VERSION 5.7 ;
  NOWIREEXTENSIONATPIN ON ;
  DIVIDERCHAR "/" ;
  BUSBITCHARS "[]" ;
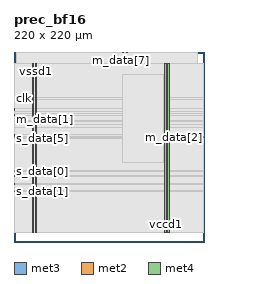
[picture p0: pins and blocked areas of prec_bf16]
MACRO prec_bf16
  CLASS BLOCK ;
  FOREIGN prec_bf16 ;
  ORIGIN 0.000 0.000 ;
  SIZE 220.000 BY 220.000 ;
  PIN clk
    DIRECTION INPUT ;
    USE SIGNAL ;
    ANTENNAGATEAREA 1.286700 ;
    ANTENNADIFFAREA 0.434700 ;
    PORT
      LAYER met3 ;
        RECT 0.000 165.960 0.600 166.560 ;
    END
  END clk
  PIN m_data[0]
    DIRECTION OUTPUT ;
    USE SIGNAL ;
    ANTENNADIFFAREA 0.795200 ;
    PORT
      LAYER met2 ;
        RECT 125.210 219.720 125.490 220.000 ;
    END
  END m_data[0]
  PIN m_data[1]
    DIRECTION OUTPUT ;
    USE SIGNAL ;
    ANTENNADIFFAREA 0.795200 ;
    PORT
      LAYER met3 ;
        RECT 0.000 151.000 0.600 151.600 ;
    END
  END m_data[1]
  PIN m_data[2]
    DIRECTION OUTPUT ;
    USE SIGNAL ;
    ANTENNADIFFAREA 0.795200 ;
    PORT
      LAYER met3 ;
        RECT 219.400 121.080 220.000 121.680 ;
    END
  END m_data[2]
  PIN m_data[3]
    DIRECTION OUTPUT ;
    USE SIGNAL ;
    ANTENNADIFFAREA 0.795200 ;
    PORT
      LAYER met2 ;
        RECT 130.730 219.720 131.010 220.000 ;
    END
  END m_data[3]
  PIN m_data[4]
    DIRECTION OUTPUT ;
    USE SIGNAL ;
    ANTENNADIFFAREA 0.795200 ;
    PORT
      LAYER met2 ;
        RECT 126.130 219.720 126.410 220.000 ;
    END
  END m_data[4]
  PIN m_data[5]
    DIRECTION OUTPUT ;
    USE SIGNAL ;
    ANTENNADIFFAREA 0.795200 ;
    PORT
      LAYER met2 ;
        RECT 129.810 219.720 130.090 220.000 ;
    END
  END m_data[5]
  PIN m_data[6]
    DIRECTION OUTPUT ;
    USE SIGNAL ;
    ANTENNADIFFAREA 0.795200 ;
    PORT
      LAYER met2 ;
        RECT 116.010 219.720 116.290 220.000 ;
    END
  END m_data[6]
  PIN m_data[7]
    DIRECTION OUTPUT ;
    USE SIGNAL ;
    ANTENNADIFFAREA 0.795200 ;
    PORT
      LAYER met2 ;
        RECT 124.290 219.720 124.570 220.000 ;
    END
  END m_data[7]
  PIN m_last
    DIRECTION OUTPUT ;
    USE SIGNAL ;
    ANTENNADIFFAREA 0.795200 ;
    PORT
      LAYER met3 ;
        RECT 0.000 152.360 0.600 152.960 ;
    END
  END m_last
  PIN m_ready
    DIRECTION INPUT ;
    USE SIGNAL ;
    ANTENNAGATEAREA 0.647700 ;
    ANTENNADIFFAREA 0.434700 ;
    PORT
      LAYER met3 ;
        RECT 0.000 146.920 0.600 147.520 ;
    END
  END m_ready
  PIN m_valid
    DIRECTION OUTPUT ;
    USE SIGNAL ;
    ANTENNADIFFAREA 0.795200 ;
    PORT
      LAYER met3 ;
        RECT 0.000 153.720 0.600 154.320 ;
    END
  END m_valid
  PIN rst
    DIRECTION INPUT ;
    USE SIGNAL ;
    ANTENNAGATEAREA 0.647700 ;
    ANTENNADIFFAREA 0.434700 ;
    PORT
      LAYER met3 ;
        RECT 0.000 148.280 0.600 148.880 ;
    END
  END rst
  PIN s_data[0]
    DIRECTION INPUT ;
    USE SIGNAL ;
    ANTENNAGATEAREA 0.647700 ;
    ANTENNADIFFAREA 0.434700 ;
    PORT
      LAYER met3 ;
        RECT 0.000 81.640 0.600 82.240 ;
    END
  END s_data[0]
  PIN s_data[1]
    DIRECTION INPUT ;
    USE SIGNAL ;
    ANTENNAGATEAREA 0.647700 ;
    ANTENNADIFFAREA 0.434700 ;
    PORT
      LAYER met3 ;
        RECT 0.000 66.680 0.600 67.280 ;
    END
  END s_data[1]
  PIN s_data[2]
    DIRECTION INPUT ;
    USE SIGNAL ;
    ANTENNAGATEAREA 0.647700 ;
    ANTENNADIFFAREA 0.434700 ;
    PORT
      LAYER met3 ;
        RECT 0.000 76.200 0.600 76.800 ;
    END
  END s_data[2]
  PIN s_data[3]
    DIRECTION INPUT ;
    USE SIGNAL ;
    ANTENNAGATEAREA 0.647700 ;
    ANTENNADIFFAREA 0.434700 ;
    PORT
      LAYER met3 ;
        RECT 0.000 58.520 0.600 59.120 ;
    END
  END s_data[3]
  PIN s_data[4]
    DIRECTION INPUT ;
    USE SIGNAL ;
    ANTENNAGATEAREA 0.647700 ;
    ANTENNADIFFAREA 0.434700 ;
    PORT
      LAYER met3 ;
        RECT 0.000 123.800 0.600 124.400 ;
    END
  END s_data[4]
  PIN s_data[5]
    DIRECTION INPUT ;
    USE SIGNAL ;
    ANTENNAGATEAREA 0.647700 ;
    ANTENNADIFFAREA 0.434700 ;
    PORT
      LAYER met3 ;
        RECT 0.000 119.720 0.600 120.320 ;
    END
  END s_data[5]
  PIN s_data[6]
    DIRECTION INPUT ;
    USE SIGNAL ;
    ANTENNAGATEAREA 0.647700 ;
    ANTENNADIFFAREA 0.434700 ;
    PORT
      LAYER met3 ;
        RECT 0.000 121.080 0.600 121.680 ;
    END
  END s_data[6]
  PIN s_data[7]
    DIRECTION INPUT ;
    USE SIGNAL ;
    ANTENNAGATEAREA 0.647700 ;
    ANTENNADIFFAREA 0.434700 ;
    PORT
      LAYER met3 ;
        RECT 0.000 122.440 0.600 123.040 ;
    END
  END s_data[7]
  PIN s_last
    DIRECTION INPUT ;
    USE SIGNAL ;
    ANTENNAGATEAREA 0.647700 ;
    ANTENNADIFFAREA 0.434700 ;
    PORT
      LAYER met3 ;
        RECT 0.000 133.320 0.600 133.920 ;
    END
  END s_last
  PIN s_ready
    DIRECTION OUTPUT ;
    USE SIGNAL ;
    ANTENNADIFFAREA 0.795200 ;
    PORT
      LAYER met3 ;
        RECT 0.000 140.120 0.600 140.720 ;
    END
  END s_ready
  PIN s_valid
    DIRECTION INPUT ;
    USE SIGNAL ;
    ANTENNAGATEAREA 0.647700 ;
    ANTENNADIFFAREA 0.434700 ;
    PORT
      LAYER met3 ;
        RECT 0.000 134.680 0.600 135.280 ;
    END
  END s_valid
  PIN vccd1
    DIRECTION INOUT ;
    USE POWER ;
    PORT
      LAYER met4 ;
        RECT 21.040 10.640 22.640 206.960 ;
    END
    PORT
      LAYER met4 ;
        RECT 174.640 10.640 176.240 206.960 ;
    END
  END vccd1
  PIN vssd1
    DIRECTION INOUT ;
    USE GROUND ;
    PORT
      LAYER met4 ;
        RECT 24.340 10.640 25.940 206.960 ;
    END
    PORT
      LAYER met4 ;
        RECT 177.940 10.640 179.540 206.960 ;
    END
  END vssd1
  OBS
      LAYER nwell ;
        RECT 5.330 10.795 214.550 206.805 ;
      LAYER li1 ;
        RECT 5.520 10.795 214.360 206.805 ;
      LAYER met1 ;
        RECT 2.830 10.640 214.360 206.960 ;
      LAYER met2 ;
        RECT 2.850 219.440 115.730 219.720 ;
        RECT 116.570 219.440 124.010 219.720 ;
        RECT 124.850 219.440 124.930 219.720 ;
        RECT 125.770 219.440 125.850 219.720 ;
        RECT 126.690 219.440 129.530 219.720 ;
        RECT 130.370 219.440 130.450 219.720 ;
        RECT 131.290 219.440 212.890 219.720 ;
        RECT 2.850 10.695 212.890 219.440 ;
      LAYER met3 ;
        RECT 0.600 166.960 219.400 206.885 ;
        RECT 1.000 165.560 219.400 166.960 ;
        RECT 0.600 154.720 219.400 165.560 ;
        RECT 1.000 150.600 219.400 154.720 ;
        RECT 0.600 149.280 219.400 150.600 ;
        RECT 1.000 146.520 219.400 149.280 ;
        RECT 0.600 141.120 219.400 146.520 ;
        RECT 1.000 139.720 219.400 141.120 ;
        RECT 0.600 135.680 219.400 139.720 ;
        RECT 1.000 132.920 219.400 135.680 ;
        RECT 0.600 124.800 219.400 132.920 ;
        RECT 1.000 122.080 219.400 124.800 ;
        RECT 1.000 120.680 219.000 122.080 ;
        RECT 1.000 119.320 219.400 120.680 ;
        RECT 0.600 82.640 219.400 119.320 ;
        RECT 1.000 81.240 219.400 82.640 ;
        RECT 0.600 77.200 219.400 81.240 ;
        RECT 1.000 75.800 219.400 77.200 ;
        RECT 0.600 67.680 219.400 75.800 ;
        RECT 1.000 66.280 219.400 67.680 ;
        RECT 0.600 59.520 219.400 66.280 ;
        RECT 1.000 58.120 219.400 59.520 ;
        RECT 0.600 10.715 219.400 58.120 ;
      LAYER met4 ;
        RECT 125.415 91.975 173.585 193.625 ;
  END
END prec_bf16
END LIBRARY

